VERSION 5.7 ;
  NOWIREEXTENSIONATPIN ON ;
  DIVIDERCHAR "/" ;
  BUSBITCHARS "[]" ;
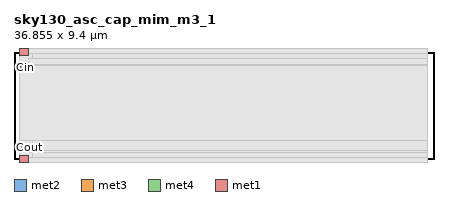
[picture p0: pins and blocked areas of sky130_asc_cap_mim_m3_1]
MACRO sky130_asc_cap_mim_m3_1
  CLASS CORE ;
  FOREIGN sky130_asc_cap_mim_m3_1 ;
  ORIGIN 0.000 0.000 ;
  SIZE 36.855 BY 9.400 ;
  SITE unitasc ;
  PIN Cin
    DIRECTION INOUT ;
    PORT
      LAYER met2 ;
        RECT 0.550 7.900 1.350 8.200 ;
      LAYER met3 ;
        RECT 0.550 7.900 1.350 8.200 ;
    END
  END Cin
  PIN Cout
    DIRECTION INOUT ;
    PORT
      LAYER met4 ;
        RECT 0.660 0.850 1.260 1.250 ;
    END
  END Cout
  PIN VPWR
    DIRECTION INOUT ;
    USE POWER ;
    PORT
      LAYER met1 ;
        RECT 0.460 9.100 1.310 9.700 ;
    END
  END VPWR
  PIN VGND
    DIRECTION INOUT ;
    USE GROUND ;
    PORT
      LAYER met1 ;
        RECT 0.460 -0.300 1.310 0.300 ;
    END
  END VGND
  OBS
      LAYER li1 ;
        RECT 0.460 -0.150 36.300 9.550 ;
      LAYER met1 ;
        RECT 1.310 9.250 36.300 9.700 ;
        RECT 1.590 8.820 36.300 9.250 ;
        RECT 1.310 0.580 36.300 8.820 ;
        RECT 1.590 0.150 36.300 0.580 ;
        RECT 1.310 -0.300 36.300 0.150 ;
      LAYER met2 ;
        RECT 0.450 0.800 1.450 8.250 ;
      LAYER met3 ;
        RECT 0.450 0.750 36.310 8.250 ;
      LAYER met4 ;
        RECT 0.460 1.650 36.300 8.190 ;
        RECT 1.660 0.750 36.300 1.650 ;
  END
END sky130_asc_cap_mim_m3_1
END LIBRARY

